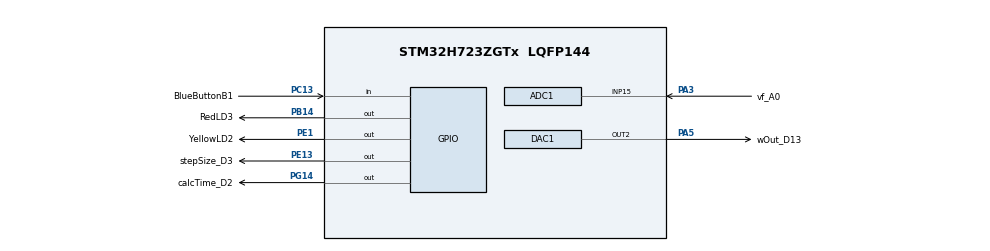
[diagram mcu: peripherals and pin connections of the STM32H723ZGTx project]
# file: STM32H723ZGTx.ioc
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ADC1.Channel-1\#ChannelRegularConversion=ADC_CHANNEL_15
ADC1.NbrOfConversionFlag=1
ADC1.OffsetNumber-1\#ChannelRegularConversion=ADC_OFFSET_NONE
ADC1.OffsetSignedSaturation-1\#ChannelRegularConversion=DISABLE
ADC1.Rank-1\#ChannelRegularConversion=1
ADC1.SamplingTime-1\#ChannelRegularConversion=ADC_SAMPLETIME_1CYCLE_5
ADC1.master=1
CORTEX_M7.default_mode_Activation=1
DAC1.DAC_Channel-DAC_OUT2=DAC_CHANNEL_2
Mcu.Family=STM32H7
Mcu.Name=STM32H723ZGTx
Mcu.Package=LQFP144
NVIC.PriorityGroup=NVIC_PRIORITYGROUP_4
NVIC.TIM2_IRQn=true\:0\:0\:false\:false\:true\:true\:true\:true
PA13(JTMS/SWDIO).GPIO_Label=SWDIO
PA13(JTMS/SWDIO).Signal=DEBUG_JTMS-SWDIO
PA14(JTCK/SWCLK).GPIO_Label=SWCLK
PA14(JTCK/SWCLK).Signal=DEBUG_JTCK-SWCLK
PA3.GPIO_Label=vf_A0
PA3.Signal=ADCx_INP15
PA5.GPIO_Label=wOut_D13
PA5.Signal=COMP_DAC12_group
PB14.GPIO_Label=RedLD3
PB14.Signal=GPIO_Output
PC13.GPIO_Label=BlueButtonB1
PC13.Signal=GPIO_Input
PC14-OSC32_IN.Signal=RCC_OSC32_IN
PC15-OSC32_OUT.Signal=RCC_OSC32_OUT
PE1.GPIO_Label=YellowLD2
PE1.Signal=GPIO_Output
PE13.GPIO_Label=stepSize_D3
PE13.GPIO_Speed=GPIO_SPEED_FREQ_VERY_HIGH
PE13.Signal=GPIO_Output
PG14.GPIO_Label=calcTime_D2
PG14.GPIO_Speed=GPIO_SPEED_FREQ_VERY_HIGH
PG14.Signal=GPIO_Output
ProjectManager.HeapSize=0x200
ProjectManager.StackSize=0x400
ProjectManager.TargetToolchain=STM32CubeIDE
RCC.ADCFreq_Value=96000000
RCC.APB1Freq_Value=137500000
RCC.APB2Freq_Value=137500000
RCC.APB3Freq_Value=137500000
RCC.APB4Freq_Value=137500000
RCC.CortexFreq_Value=275000000
RCC.D1PPRE=RCC_APB3_DIV2
RCC.D2PPRE1=RCC_APB1_DIV2
RCC.D2PPRE2=RCC_APB2_DIV2
RCC.D3PPRE=RCC_APB4_DIV2
RCC.DIVM1=4
RCC.DIVM2=4
RCC.DIVN1=17
RCC.DIVN2=12
RCC.DIVP1=1
RCC.DIVQ1=4
RCC.HCLKFreq_Value=275000000
RCC.HSE_VALUE=8000000
RCC.PLL2FRACN=0
RCC.PLLFRACN=1536
RCC.SYSCLKFreq_VALUE=275000000
RCC.SYSCLKSource=RCC_SYSCLKSOURCE_PLLCLK
RCC.USBCLockSelection=RCC_USBCLKSOURCE_HSI48
RCC.USBFreq_Value=48000000
SH.ADCx_INP15.0=ADC1_INP15,IN15-Single-Ended
SH.COMP_DAC12_group.0=DAC1_OUT2,DAC_OUT2
TIM2.Channel-Output\ Compare1\ No\ Output=TIM_CHANNEL_1
TIM2.Period=199
TIM2.Prescaler=274
VP_MEMORYMAP_VS_MEMORYMAP.Mode=CurAppReg
VP_TIM2_VS_ClockSourceINT.Mode=Internal
VP_TIM2_VS_no_output1.Mode=Output Compare1 No Output
board=NUCLEO-H723ZG

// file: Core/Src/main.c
/* USER CODE BEGIN Header */
/**
  ******************************************************************************
  * @file           : main.c
  * @brief          : Main program body
  ******************************************************************************
  * @attention
  *
  * Copyright (c) 2026 STMicroelectronics.
  * All rights reserved.
  *
  * This software is licensed under terms that can be found in the LICENSE file
  * in the root directory of this software component.
  * If no LICENSE file comes with this software, it is provided AS-IS.
  *
  ******************************************************************************
  */
/* USER CODE END Header */
#include "main.h"
#include "adc.h"
#include "dac.h"
#include "tim.h"
#include "gpio.h"

/* USER CODE BEGIN Includes */
#include "block.h"
/* USER CODE END Includes */

/* USER CODE BEGIN PTD */
#define CONCAT_INNER(a, b) a##b
#define CONCAT(a, b) CONCAT_INNER(a, b)

/* Define shortcut names for unique, hash-based eFMU API: */
#define MODEL_HASH \
  Hcbd8c48e05b139646178cc6f7987b8955b6ce985_cb4a8a449b4ada864625ee5a4355578a3aaf08ed
typedef CONCAT(BlockState_, MODEL_HASH) \
  ModelGrid;
typedef CONCAT(SPE_Real_, MODEL_HASH) \
  Grid_Real;
typedef CONCAT(SPE_ErrorSignal_, MODEL_HASH) \
  Grid_ErrorSignal;

#define Grid_NONE_ERRORSIGNAL \
  CONCAT(SPE_ERRORSIGNAL_NONE_, MODEL_HASH)
#define Grid_UNSPECIFIED_ERRORSIGNAL \
  CONCAT(SPE_ERRORSIGNAL_UNSPECIFIED_ERROR_, MODEL_HASH)

#define Grid_Startup \
  CONCAT(Startup_, MODEL_HASH)
#define Grid_DoStep \
  CONCAT(DoStep_, MODEL_HASH)
#define Grid_Recalibrate \
  CONCAT(Recalibrate_, MODEL_HASH)
#define Grid_Reinitialize \
  CONCAT(Reinitialize_, MODEL_HASH)
/* USER CODE END PTD */

/* USER CODE BEGIN PV */
/* Sampling activation counter: */
static volatile uint8_t pending_samplings;
/* USER CODE END PV */

void SystemClock_Config(void);
static void MPU_Config(void);

int main(void)
{

  /* MPU Configuration--------------------------------------------------------*/
  MPU_Config();

  /* MCU Configuration--------------------------------------------------------*/

  /* Reset of all peripherals, Initializes the Flash interface and the Systick. */
  HAL_Init();

  /* Configure the system clock */
  SystemClock_Config();

  /* Initialize all configured peripherals */
  MX_GPIO_Init();
  MX_ADC1_Init();
  MX_DAC1_Init();
  MX_TIM2_Init();
  /* USER CODE BEGIN 2 */
  /* Initialize error signaling: */
  Grid_ErrorSignal error_signals = Grid_NONE_ERRORSIGNAL;
  uint32_t error_signal_timestamp = ((uint32_t) 0);
  uint32_t error_overrun_timestamp = ((uint32_t) 0);

  /* Pre-compute constants: */
  const uint32_t POLL_TIMEOUT =
   ((uint32_t) 1); /* in ms */
  const Grid_Real ADC_TO_VOLTS =
    ((Grid_Real) 3.3) / ((Grid_Real) 65535.0 /* 16-bit ADC */);
  const Grid_Real VOLTS_TO_DAC =
    ((Grid_Real) 4095.0) / ((Grid_Real) 3.3);
  const Grid_Real DAC_MAX =
    ((Grid_Real) 4095.0);
  const Grid_Real DAC_MIN =
    ((Grid_Real) 0.0);
  const Grid_Real VF_OFFSET =
    ((Grid_Real) 1.5);

  /* Initialize the eFMU: */
  ModelGrid grid;
  Grid_Startup(&grid);
  error_signals |= grid.ErrorSignals;
  if (Grid_NONE_ERRORSIGNAL != error_signals)
  { /* Block and blink the error LED if initialization failed: */
    while (true)
    {
      HAL_GPIO_WritePin(RedLD3_GPIO_Port, RedLD3_Pin, GPIO_PIN_SET);
      uint32_t start = HAL_GetTick();
      while ((HAL_GetTick() - start) < ((uint32_t) 2000))
      {
      }
      HAL_GPIO_WritePin(RedLD3_GPIO_Port, RedLD3_Pin, GPIO_PIN_RESET);
      start = HAL_GetTick();
      while ((HAL_GetTick() - start) < ((uint32_t) 2000))
      {
      }
    }
  }

  /* Start the sampling timer and DAC channels: */
  pending_samplings = ((uint8_t) 0);
  HAL_DAC_Start(&hdac1, DAC_CHANNEL_2);
  HAL_TIM_Base_Start_IT(&htim2);
  __enable_irq();
  /* USER CODE END 2 */

  /* Infinite loop */
  while (1)
  {

    /* USER CODE BEGIN 3 */
    /*
      Conduct sampling if the sampling timer ticked:
    */
    if (pending_samplings > ((uint8_t) 0))
    {
      /* Always reset the error signals: */
      error_signals = Grid_NONE_ERRORSIGNAL;

      /* Provide computation time feedback for external profiling: */
      HAL_GPIO_WritePin(calcTime_D2_GPIO_Port, calcTime_D2_Pin, GPIO_PIN_SET);

      /* Digital input processing: */
      grid.fault = (GPIO_PIN_SET == HAL_GPIO_ReadPin(
    	BlueButtonB1_GPIO_Port,
        BlueButtonB1_Pin));

      /* Analog input processing: */
      HAL_ADC_Start(&hadc1);
      if (HAL_OK == HAL_ADC_PollForConversion(&hadc1, POLL_TIMEOUT))
      {
        const uint32_t adc_raw = HAL_ADC_GetValue(&hadc1);
        grid.vf = (((Grid_Real) adc_raw) * ADC_TO_VOLTS) - VF_OFFSET;
      }
      else
      {
        error_signals |= Grid_UNSPECIFIED_ERRORSIGNAL;
      }
      HAL_ADC_Stop(&hadc1);

      /* Compute sampling step: */
      Grid_DoStep(&grid);
      error_signals |= grid.ErrorSignals;

      /* Output processing (scaling, clamping, converting volt to AC): */
      Grid_Real dac_w_val = grid.w * VOLTS_TO_DAC;
      if (DAC_MIN > dac_w_val)
      {
        dac_w_val = DAC_MIN;
      }
      else if (DAC_MAX < dac_w_val)
      {
        dac_w_val = DAC_MAX;
      }
      HAL_DAC_SetValue(
        &hdac1,
        DAC_CHANNEL_2,
        DAC_ALIGN_12B_R,
        ((uint32_t) dac_w_val));

      /* Provide computation time feedback for external profiling: */
      HAL_GPIO_WritePin(calcTime_D2_GPIO_Port, calcTime_D2_Pin, GPIO_PIN_RESET);

      --pending_samplings;
    }

    /*
      Check if any errors are signaled from the last sampling, or an overrun
      occurred; if so, set the error LED on. Also check if enough time has
      passed since the last error occurred; if so, turn off the LED:
    */
    const uint8_t tick = HAL_GetTick();

    if (Grid_NONE_ERRORSIGNAL != error_signals)
    {
      error_signal_timestamp = tick;
      HAL_GPIO_WritePin(RedLD3_GPIO_Port, RedLD3_Pin, GPIO_PIN_SET);
    }
    if (pending_samplings > ((uint8_t) 1))
    {
      error_overrun_timestamp = tick;
      HAL_GPIO_WritePin(YellowLD2_GPIO_Port, YellowLD2_Pin, GPIO_PIN_SET);
    }

    if ((((uint32_t) 0) != error_signal_timestamp)
      && (((uint32_t) 30000) < (tick - error_signal_timestamp)))
    {
      HAL_GPIO_WritePin(RedLD3_GPIO_Port, RedLD3_Pin, GPIO_PIN_RESET);
      error_signal_timestamp = ((uint32_t) 0);
    }
    if ((((uint32_t) 0) != error_overrun_timestamp)
      && (((uint32_t) 5000) < (tick - error_overrun_timestamp)))
    {
      HAL_GPIO_WritePin(YellowLD2_GPIO_Port, YellowLD2_Pin, GPIO_PIN_RESET);
      error_overrun_timestamp = ((uint32_t) 0);
    }
  }
  /* USER CODE END 3 */
}

void SystemClock_Config(void)
{
  RCC_OscInitTypeDef RCC_OscInitStruct = {0};
  RCC_ClkInitTypeDef RCC_ClkInitStruct = {0};

  /** Supply configuration update enable
  */
  HAL_PWREx_ConfigSupply(PWR_LDO_SUPPLY);

  /** Configure the main internal regulator output voltage
  */
  __HAL_PWR_VOLTAGESCALING_CONFIG(PWR_REGULATOR_VOLTAGE_SCALE0);

  while(!__HAL_PWR_GET_FLAG(PWR_FLAG_VOSRDY)) {}

  /** Initializes the RCC Oscillators according to the specified parameters
  * in the RCC_OscInitTypeDef structure.
  */
  RCC_OscInitStruct.OscillatorType = RCC_OSCILLATORTYPE_HSI;
  RCC_OscInitStruct.HSIState = RCC_HSI_DIV1;
  RCC_OscInitStruct.HSICalibrationValue = 64;
  RCC_OscInitStruct.PLL.PLLState = RCC_PLL_ON;
  RCC_OscInitStruct.PLL.PLLSource = RCC_PLLSOURCE_HSI;
  RCC_OscInitStruct.PLL.PLLM = 4;
  RCC_OscInitStruct.PLL.PLLN = 34;
  RCC_OscInitStruct.PLL.PLLP = 1;
  RCC_OscInitStruct.PLL.PLLQ = 4;
  RCC_OscInitStruct.PLL.PLLR = 2;
  RCC_OscInitStruct.PLL.PLLRGE = RCC_PLL1VCIRANGE_3;
  RCC_OscInitStruct.PLL.PLLVCOSEL = RCC_PLL1VCOWIDE;
  RCC_OscInitStruct.PLL.PLLFRACN = 3072;
  if (HAL_RCC_OscConfig(&RCC_OscInitStruct) != HAL_OK)
  {
    Error_Handler();
  }

  /** Initializes the CPU, AHB and APB buses clocks
  */
  RCC_ClkInitStruct.ClockType = RCC_CLOCKTYPE_HCLK|RCC_CLOCKTYPE_SYSCLK
                              |RCC_CLOCKTYPE_PCLK1|RCC_CLOCKTYPE_PCLK2
                              |RCC_CLOCKTYPE_D3PCLK1|RCC_CLOCKTYPE_D1PCLK1;
  RCC_ClkInitStruct.SYSCLKSource = RCC_SYSCLKSOURCE_PLLCLK;
  RCC_ClkInitStruct.SYSCLKDivider = RCC_SYSCLK_DIV1;
  RCC_ClkInitStruct.AHBCLKDivider = RCC_HCLK_DIV2;
  RCC_ClkInitStruct.APB3CLKDivider = RCC_APB3_DIV2;
  RCC_ClkInitStruct.APB1CLKDivider = RCC_APB1_DIV2;
  RCC_ClkInitStruct.APB2CLKDivider = RCC_APB2_DIV2;
  RCC_ClkInitStruct.APB4CLKDivider = RCC_APB4_DIV2;

  if (HAL_RCC_ClockConfig(&RCC_ClkInitStruct, FLASH_LATENCY_3) != HAL_OK)
  {
    Error_Handler();
  }
}

/* USER CODE BEGIN 4 */
void HAL_TIM_PeriodElapsedCallback(TIM_HandleTypeDef *htim)
{
  if (TIM2 == htim->Instance)
  {
    if (pending_samplings < ((uint8_t) 255))
    {
      ++pending_samplings;
    }
    HAL_GPIO_TogglePin(stepSize_D3_GPIO_Port, stepSize_D3_Pin);
  }
}
/* USER CODE END 4 */

 /* MPU Configuration */

void MPU_Config(void)
{
  MPU_Region_InitTypeDef MPU_InitStruct = {0};

  /* Disables the MPU */
  HAL_MPU_Disable();

  /** Initializes and configures the Region and the memory to be protected
  */
  MPU_InitStruct.Enable = MPU_REGION_ENABLE;
  MPU_InitStruct.Number = MPU_REGION_NUMBER0;
  MPU_InitStruct.BaseAddress = 0x0;
  MPU_InitStruct.Size = MPU_REGION_SIZE_4GB;
  MPU_InitStruct.SubRegionDisable = 0x87;
  MPU_InitStruct.TypeExtField = MPU_TEX_LEVEL0;
  MPU_InitStruct.AccessPermission = MPU_REGION_NO_ACCESS;
  MPU_InitStruct.DisableExec = MPU_INSTRUCTION_ACCESS_DISABLE;
  MPU_InitStruct.IsShareable = MPU_ACCESS_SHAREABLE;
  MPU_InitStruct.IsCacheable = MPU_ACCESS_NOT_CACHEABLE;
  MPU_InitStruct.IsBufferable = MPU_ACCESS_NOT_BUFFERABLE;

  HAL_MPU_ConfigRegion(&MPU_InitStruct);
  /* Enables the MPU */
  HAL_MPU_Enable(MPU_PRIVILEGED_DEFAULT);

}

void Error_Handler(void)
{
  __disable_irq();
  while (1)
  {
  }
}
